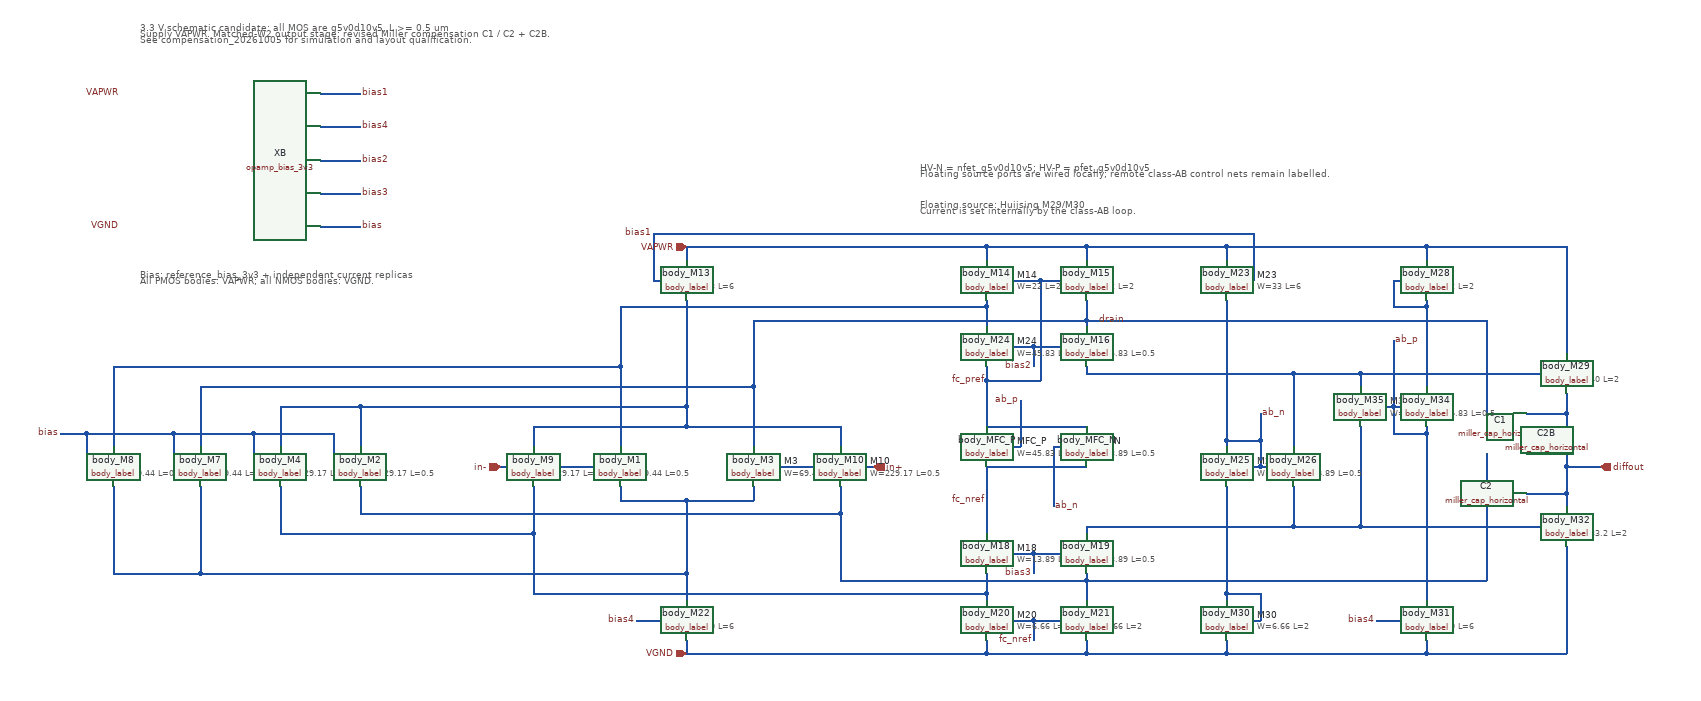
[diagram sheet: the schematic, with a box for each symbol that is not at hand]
v {xschem version=3.4.5 file_version=1.2
}
G {}
K {}
V {}
S {}
E {}
N -230 -60 -230 -30 {
lab=#net1}
N 0 -60 230 -60 {
lab=#net1}
N 230 -60 230 -30 {
lab=#net1}
N 0 -90 0 -60 {
lab=#net1}
N -490 -90 0 -90 {
lab=#net1}
N -490 -90 -490 -30 {
lab=#net1}
N -610 -90 -490 -90 {
lab=#net1}
N -610 -90 -610 -30 {
lab=#net1}
N -100 -150 -100 -30 {
lab=#net2}
N -860 -150 -100 -150 {
lab=#net2}
N -860 -150 -860 -30 {
lab=#net2}
N -730 -120 -730 -30 {
lab=drain}
N -730 -120 100 -120 {
lab=drain}
N 100 -120 100 -30 {
lab=drain}
N -100 30 -100 50 {
lab=#net3}
N 0 50 0 160 {
lab=#net3}
N -730 160 0 160 {
lab=#net3}
N -730 30 -730 160 {
lab=#net3}
N -280 0 -240 0 {
lab=in-}
N -240 0 -240 10 {
lab=in-}
N -240 10 -220 10 {
lab=in-}
N -220 10 -220 0 {
lab=in-}
N -220 0 -140 0 {
lab=in-}

N -490 70 230 70 {
lab=#net4}
N 230 70 230 170 {
lab=#net4}
N -610 30 -610 100 {
lab=#net5}
N -610 100 -230 100 {
lab=#net5}
N -230 30 -230 100 {
lab=#net5}
N 0 -250 0 -90 {
lab=#net1}
N 530 -280 560 -280 {
lab=#net6}
N 450 -240 450 -200 {
lab=#net2}
N 600 -220 600 -210 {
lab=drain}
N 530 -280 530 -130 {
lab=#net6}
N 450 190 450 200 {
lab=#net5}
N 600 170 600 200 {
lab=#net4}
N 0 160 0 200 {
lab=#net3}
N 0 260 0 280 {
lab=VGND}
N 450 280 600 280 {
lab=VGND}
N 600 260 600 280 {
lab=VGND}
N 450 260 450 280 {
lab=VGND}
N 450 -330 450 -310 {
lab=VAPWR}
N 450 -330 600 -330 {
lab=VAPWR}
N 600 -330 600 -310 {
lab=VAPWR}
N 600 -330 810 -330 {
lab=VAPWR}
N 810 -330 810 -310 {
lab=VAPWR}
N 810 -330 1110 -330 {
lab=VAPWR}
N 1060 -280 1070 -280 {
lab=#net7}
N 1060 -280 1060 -240 {
lab=#net7}
N 1060 -240 1110 -240 {
lab=#net7}
N 1110 -250 1110 -240 {
lab=#net7}
N 810 -250 810 -40 {
lab=#net8}
N 860 0 870 0 {
lab=#net8}
N 860 -40 860 0 {
lab=#net8}
N 810 -40 860 -40 {
lab=#net8}
N 1060 -90 1070 -90 {
lab=#net9}
N 1110 -240 1110 -120 {
lab=#net7}
N 1060 -90 1060 -50 {
lab=#net9}
N 1060 -50 1110 -50 {
lab=#net9}
N 1110 -60 1110 -50 {
lab=#net9}
N 450 -130 530 -130 {
lab=#net6}
N 1110 -330 1110 -310 {
lab=VAPWR}
N 600 -150 600 -140 {
lab=#net10}
N 1010 -140 1280 -140 {
lab=#net10}
N -230 -60 0 -60 {
lab=#net1}
N -100 50 0 50 {
lab=#net3}
N 490 -280 530 -280 {
lab=#net6}
N 0 280 450 280 {
lab=VGND}
N 450 -150 450 -130 {
lab=#net6}
N 810 -40 810 -30 {
lab=#net8}
N 810 190 810 200 {
lab=#net11}
N 600 280 810 280 {
lab=VGND}
N 810 260 810 280 {
lab=VGND}
N 1110 -50 1110 200 {
lab=#net9}
N 1110 280 1320 280 {
lab=VGND}
N 1320 120 1320 280 {
lab=VGND}
N 1320 40 1320 60 {
lab=diffout}
N 1320 -330 1320 -170 {
lab=VAPWR}
N 1110 -330 1320 -330 {
lab=VAPWR}
N 1110 260 1110 280 {
lab=VGND}
N 850 -350 850 -280 {
lab=bias1}
N -50 -350 850 -350 {
lab=bias1}
N 0 -330 0 -310 {
lab=VAPWR}
N 0 -330 450 -330 {
lab=VAPWR}
N -50 -350 -50 -280 {
lab=bias1}
N -50 -280 -40 -280 {
lab=bias1}
N 600 90 600 100 {
lab=#net12}
N 600 90 910 90 {
lab=#net12}
N 910 30 910 90 {
lab=#net12}
N 1010 -60 1010 90 {
lab=#net12}
N 850 230 860 230 {
lab=#net11}
N 860 190 860 230 {
lab=#net11}
N 810 190 860 190 {
lab=#net11}
N 600 170 1200 170 {
lab=#net4}
N 600 -220 1200 -220 {
lab=drain}
N 1010 -140 1010 -120 {
lab=#net10}
N 910 -140 910 -30 {
lab=#net10}
N 140 0 220 0 {
lab=in+}
N 220 0 220 10 {
lab=in+}
N 220 10 240 10 {
lab=in+}
N 240 10 240 0 {
lab=in+}
N 240 0 280 0 {
lab=in+}

N 100 -220 100 -120 {
lab=drain}
N 100 -220 600 -220 {
lab=drain}
N -100 -240 -100 -150 {
lab=#net2}
N -100 -240 450 -240 {
lab=#net2}
N -230 100 -230 190 {
lab=#net5}
N -230 190 450 190 {
lab=#net5}
N 0 50 100 50 {
lab=#net3}
N 100 30 100 50 {
lab=#net3}
N -490 30 -490 70 {
lab=#net4}
N 230 30 230 70 {
lab=#net4}
N 810 280 1110 280 {
lab=VGND}
N 910 90 1010 90 {
lab=#net12}
N 810 30 810 190 {
lab=#net11}
N 600 160 600 170 {
lab=#net4}
N 600 -250 600 -220 {
lab=drain}
N 910 -140 1010 -140 {
lab=#net10}
N 600 -140 910 -140 {
lab=#net10}
N 450 -250 450 -240 {
lab=#net2}
N 450 160 450 190 {
lab=#net5}
N -860 30 -860 160 {
lab=#net3}
N -860 160 -730 160 {
lab=#net3}
N 1200 40 1200 170 {
lab=#net4}
N 1260 40 1320 40 {
lab=diffout}
N 1200 -220 1200 -80 {
lab=drain}
N 1260 -80 1320 -80 {
lab=diffout}
N 1320 0 1370 0 {
lab=diffout}
N 1320 0 1320 40 {
lab=diffout}
N 1320 -110 1320 -80 {
lab=diffout}
N 1320 -80 1320 0 {
lab=diffout}
N 230 170 600 170 {
lab=#net4}
N 1010 90 1280 90 {
lab=#net12}
N 1050 -90 1060 -90 {
lab=#net9}
N 850 0 860 -0 {
lab=#net8}
N 490 -180 520 -180 {lab=bias2}
N 520 -180 560 -180 {lab=bias2}
N 520 -180 520 -150 {lab=bias2}
N 490 130 520 130 {lab=bias3}
N 520 130 560 130 {lab=bias3}
N 520 130 520 160 {lab=bias3}
N 490 230 520 230 {lab=fc_nref}
N 520 230 560 230 {lab=fc_nref}
N 520 230 520 260 {lab=fc_nref}
N -550 -560 -490 -560 {lab=bias1}
N -550 -510 -490 -510 {lab=bias4}
N -550 -460 -490 -460 {lab=bias2}
N -550 -410 -490 -410 {lab=bias3}
N -550 -360 -490 -360 {lab=bias}
N -40 230 -75 230 {lab=bias4}
N 1070 230 1035 230 {lab=bias4}
N 450 -130 450 -60 {lab=fc_pref}
N 450 -60 600 -60 {lab=fc_pref}
N 450 0 600 0 {lab=fc_nref}
N 450 0 450 50 {lab=fc_nref}
N 450 50 450 100 {lab=fc_nref}
N 490 -30 500 -30 {lab=ab_p}
N 500 -30 500 -100 {lab=ab_p}
N 560 -30 550 -30 {lab=ab_n}
N 550 -30 550 60 {lab=ab_n}
N 860 -40 860 -80 {lab=ab_n}
N 1060 -90 1060 -190 {lab=ab_p}
N -940 -50 -900 -50 {lab=bias}
N -900 -50 -770 -50 {lab=bias}
N -770 -50 -650 -50 {lab=bias}
N -650 -50 -530 -50 {lab=bias}
N -900 -50 -900 0 {lab=bias}
N -770 -50 -770 0 {lab=bias}
N -650 -50 -650 0 {lab=bias}
N -530 -50 -530 0 {lab=bias}
C {hv_nmos.sym} -120 0 0 0 {name=M1
L=0.5
W=69.44
nf=5
mult=1
body=VGND
ad="'int((nf+1)/2) * W/nf * 0.29'" 
pd="'2*int((nf+1)/2) * (W/nf + 0.29)'"
as="'int((nf+2)/2) * W/nf * 0.29'" 
ps="'2*int((nf+2)/2) * (W/nf + 0.29)'"
nrd="'0.29 / W'" nrs="'0.29 / W'"
sa=0 sb=0 sd=0
model=nfet_g5v0d10v5
spiceprefix=X
}
C {hv_nmos.sym} 120 0 0 1 {name=M3
L=0.5
W=69.44
nf=5
mult=1
body=VGND
ad="'int((nf+1)/2) * W/nf * 0.29'" 
pd="'2*int((nf+1)/2) * (W/nf + 0.29)'"
as="'int((nf+2)/2) * W/nf * 0.29'" 
ps="'2*int((nf+2)/2) * (W/nf + 0.29)'"
nrd="'0.29 / W'" nrs="'0.29 / W'"
sa=0 sb=0 sd=0
model=nfet_g5v0d10v5
spiceprefix=X
}
C {hv_nmos.sym} -750 0 0 0 {name=M7
L=0.5
W=69.44
nf=5
mult=1
body=VGND
ad="'int((nf+1)/2) * W/nf * 0.29'" 
pd="'2*int((nf+1)/2) * (W/nf + 0.29)'"
as="'int((nf+2)/2) * W/nf * 0.29'" 
ps="'2*int((nf+2)/2) * (W/nf + 0.29)'"
nrd="'0.29 / W'" nrs="'0.29 / W'"
sa=0 sb=0 sd=0
model=nfet_g5v0d10v5
spiceprefix=X
}
C {hv_nmos.sym} -880 0 0 0 {name=M8
L=0.5
W=69.44
nf=5
mult=1
body=VGND
ad="'int((nf+1)/2) * W/nf * 0.29'" 
pd="'2*int((nf+1)/2) * (W/nf + 0.29)'"
as="'int((nf+2)/2) * W/nf * 0.29'" 
ps="'2*int((nf+2)/2) * (W/nf + 0.29)'"
nrd="'0.29 / W'" nrs="'0.29 / W'"
sa=0 sb=0 sd=0
model=nfet_g5v0d10v5
spiceprefix=X
}
C {devices/ipin.sym} -280 0 0 0 {name=p1 lab=in-}
C {devices/ipin.sym} 280 0 0 1 {name=p2 lab=in+

}
C {hv_nmos.sym} 470 130 0 1 {name=M18
L=0.5
W=13.89
nf=1
mult=1
body=VGND
ad="'int((nf+1)/2) * W/nf * 0.29'" 
pd="'2*int((nf+1)/2) * (W/nf + 0.29)'"
as="'int((nf+2)/2) * W/nf * 0.29'" 
ps="'2*int((nf+2)/2) * (W/nf + 0.29)'"
nrd="'0.29 / W'" nrs="'0.29 / W'"
sa=0 sb=0 sd=0
model=nfet_g5v0d10v5
spiceprefix=X
}
C {hv_nmos.sym} 580 130 0 0 {name=M19
L=0.5
W=13.89
nf=1
mult=1
body=VGND
ad="'int((nf+1)/2) * W/nf * 0.29'" 
pd="'2*int((nf+1)/2) * (W/nf + 0.29)'"
as="'int((nf+2)/2) * W/nf * 0.29'" 
ps="'2*int((nf+2)/2) * (W/nf + 0.29)'"
nrd="'0.29 / W'" nrs="'0.29 / W'"
sa=0 sb=0 sd=0
model=nfet_g5v0d10v5
spiceprefix=X
}
C {hv_nmos.sym} 470 230 0 1 {name=M20
L=2
W=6.66
nf=2
mult=1
body=VGND
ad="'int((nf+1)/2) * W/nf * 0.29'" 
pd="'2*int((nf+1)/2) * (W/nf + 0.29)'"
as="'int((nf+2)/2) * W/nf * 0.29'" 
ps="'2*int((nf+2)/2) * (W/nf + 0.29)'"
nrd="'0.29 / W'" nrs="'0.29 / W'"
sa=0 sb=0 sd=0
model=nfet_g5v0d10v5
spiceprefix=X
}
C {hv_nmos.sym} 580 230 0 0 {name=M21
L=2
W=6.66
nf=2
mult=1
body=VGND
ad="'int((nf+1)/2) * W/nf * 0.29'" 
pd="'2*int((nf+1)/2) * (W/nf + 0.29)'"
as="'int((nf+2)/2) * W/nf * 0.29'" 
ps="'2*int((nf+2)/2) * (W/nf + 0.29)'"
nrd="'0.29 / W'" nrs="'0.29 / W'"
sa=0 sb=0 sd=0
model=nfet_g5v0d10v5
spiceprefix=X
}
C {hv_nmos.sym} -20 230 0 0 {name=M22
L=6
W=10
nf=1
mult=1
body=VGND
ad="'int((nf+1)/2) * W/nf * 0.29'" 
pd="'2*int((nf+1)/2) * (W/nf + 0.29)'"
as="'int((nf+2)/2) * W/nf * 0.29'" 
ps="'2*int((nf+2)/2) * (W/nf + 0.29)'"
nrd="'0.29 / W'" nrs="'0.29 / W'"
sa=0 sb=0 sd=0
model=nfet_g5v0d10v5
spiceprefix=X
}
C {hv_nmos.sym} 830 0 0 1 {name=M25
L=0.5
W=13.89
nf=1
mult=1
body=VGND
ad="'int((nf+1)/2) * W/nf * 0.29'" 
pd="'2*int((nf+1)/2) * (W/nf + 0.29)'"
as="'int((nf+2)/2) * W/nf * 0.29'" 
ps="'2*int((nf+2)/2) * (W/nf + 0.29)'"
nrd="'0.29 / W'" nrs="'0.29 / W'"
sa=0 sb=0 sd=0
model=nfet_g5v0d10v5
spiceprefix=X
}
C {hv_nmos.sym} 890 0 0 0 {name=M26
L=0.5
W=13.89
nf=1
mult=1
body=VGND
ad="'int((nf+1)/2) * W/nf * 0.29'" 
pd="'2*int((nf+1)/2) * (W/nf + 0.29)'"
as="'int((nf+2)/2) * W/nf * 0.29'" 
ps="'2*int((nf+2)/2) * (W/nf + 0.29)'"
nrd="'0.29 / W'" nrs="'0.29 / W'"
sa=0 sb=0 sd=0
model=nfet_g5v0d10v5
spiceprefix=X
}
C {hv_nmos.sym} 830 230 0 1 {name=M30
L=2
W=6.66
nf=2
mult=1
body=VGND
ad="'int((nf+1)/2) * W/nf * 0.29'" 
pd="'2*int((nf+1)/2) * (W/nf + 0.29)'"
as="'int((nf+2)/2) * W/nf * 0.29'" 
ps="'2*int((nf+2)/2) * (W/nf + 0.29)'"
nrd="'0.29 / W'" nrs="'0.29 / W'"
sa=0 sb=0 sd=0
model=nfet_g5v0d10v5
spiceprefix=X
}
C {hv_nmos.sym} 1090 230 0 0 {name=M31
L=6
W=10
nf=1
mult=1
body=VGND
ad="'int((nf+1)/2) * W/nf * 0.29'" 
pd="'2*int((nf+1)/2) * (W/nf + 0.29)'"
as="'int((nf+2)/2) * W/nf * 0.29'" 
ps="'2*int((nf+2)/2) * (W/nf + 0.29)'"
nrd="'0.29 / W'" nrs="'0.29 / W'"
sa=0 sb=0 sd=0
model=nfet_g5v0d10v5
spiceprefix=X
}
C {hv_nmos.sym} 1300 90 0 0 {name=M32
L=2
W=133.2
nf=40
mult=1
body=VGND
ad="'int((nf+1)/2) * W/nf * 0.29'" 
pd="'2*int((nf+1)/2) * (W/nf + 0.29)'"
as="'int((nf+2)/2) * W/nf * 0.29'" 
ps="'2*int((nf+2)/2) * (W/nf + 0.29)'"
nrd="'0.29 / W'" nrs="'0.29 / W'"
sa=0 sb=0 sd=0
model=nfet_g5v0d10v5
spiceprefix=X
}
C {miller_cap_horizontal.sym} 1230 -80 0 0 {name=C1 model=cap_mim_m3_1 W=18 L=18 MF=1 spiceprefix=X}
C {miller_cap_horizontal.sym} 1230 40 0 0 {name=C2 model=cap_mim_m3_1 W=30 L=30 MF=1 spiceprefix=X}
N 1200 -20 1200 40 {lab=#net4}
N 1260 -20 1320 -20 {lab=diffout}
C {miller_cap_horizontal.sym} 1230 -20 0 0 {name=C2B model=cap_mim_m3_1 W=30 L=10 MF=1 spiceprefix=X}
C {devices/opin.sym} 1370 0 0 0 {name=p3 lab=diffout}
C {devices/iopin.sym} 0 -330 0 0 {name=p4 lab=VAPWR}
C {devices/iopin.sym} 0 280 0 0 {name=p5 lab=VGND}
C {hv_pmos.sym} -20 -280 0 0 {name=M13
L=6
W=33
body=VAPWR
nf=1
mult=1
ad="'int((nf+1)/2) * W/nf * 0.29'" 
pd="'2*int((nf+1)/2) * (W/nf + 0.29)'"
as="'int((nf+2)/2) * W/nf * 0.29'" 
ps="'2*int((nf+2)/2) * (W/nf + 0.29)'"
nrd="'0.29 / W'" nrs="'0.29 / W'"
sa=0 sb=0 sd=0
model=pfet_g5v0d10v5
spiceprefix=X
}
C {hv_pmos.sym} 470 -280 0 1 {name=M14
L=2
W=22
body=VAPWR
nf=2
mult=1
ad="'int((nf+1)/2) * W/nf * 0.29'" 
pd="'2*int((nf+1)/2) * (W/nf + 0.29)'"
as="'int((nf+2)/2) * W/nf * 0.29'" 
ps="'2*int((nf+2)/2) * (W/nf + 0.29)'"
nrd="'0.29 / W'" nrs="'0.29 / W'"
sa=0 sb=0 sd=0
model=pfet_g5v0d10v5
spiceprefix=X
}
C {hv_pmos.sym} 580 -280 0 0 {name=M15
L=2
W=22
body=VAPWR
nf=2
mult=1
ad="'int((nf+1)/2) * W/nf * 0.29'" 
pd="'2*int((nf+1)/2) * (W/nf + 0.29)'"
as="'int((nf+2)/2) * W/nf * 0.29'" 
ps="'2*int((nf+2)/2) * (W/nf + 0.29)'"
nrd="'0.29 / W'" nrs="'0.29 / W'"
sa=0 sb=0 sd=0
model=pfet_g5v0d10v5
spiceprefix=X
}
C {hv_pmos.sym} 580 -180 0 0 {name=M16
L=0.5
W=45.83
body=VAPWR
nf=1
mult=1
ad="'int((nf+1)/2) * W/nf * 0.29'" 
pd="'2*int((nf+1)/2) * (W/nf + 0.29)'"
as="'int((nf+2)/2) * W/nf * 0.29'" 
ps="'2*int((nf+2)/2) * (W/nf + 0.29)'"
nrd="'0.29 / W'" nrs="'0.29 / W'"
sa=0 sb=0 sd=0
model=pfet_g5v0d10v5
spiceprefix=X
}
C {hv_pmos.sym} 830 -280 0 1 {name=M23
L=6
W=33
body=VAPWR
nf=1
mult=1
ad="'int((nf+1)/2) * W/nf * 0.29'" 
pd="'2*int((nf+1)/2) * (W/nf + 0.29)'"
as="'int((nf+2)/2) * W/nf * 0.29'" 
ps="'2*int((nf+2)/2) * (W/nf + 0.29)'"
nrd="'0.29 / W'" nrs="'0.29 / W'"
sa=0 sb=0 sd=0
model=pfet_g5v0d10v5
spiceprefix=X
}
C {hv_pmos.sym} 470 -180 0 1 {name=M24
L=0.5
W=45.83
body=VAPWR
nf=1
mult=1
ad="'int((nf+1)/2) * W/nf * 0.29'" 
pd="'2*int((nf+1)/2) * (W/nf + 0.29)'"
as="'int((nf+2)/2) * W/nf * 0.29'" 
ps="'2*int((nf+2)/2) * (W/nf + 0.29)'"
nrd="'0.29 / W'" nrs="'0.29 / W'"
sa=0 sb=0 sd=0
model=pfet_g5v0d10v5
spiceprefix=X
}
C {hv_pmos.sym} 1090 -280 0 0 {name=M28
L=2
W=22
body=VAPWR
nf=2
mult=1
ad="'int((nf+1)/2) * W/nf * 0.29'" 
pd="'2*int((nf+1)/2) * (W/nf + 0.29)'"
as="'int((nf+2)/2) * W/nf * 0.29'" 
ps="'2*int((nf+2)/2) * (W/nf + 0.29)'"
nrd="'0.29 / W'" nrs="'0.29 / W'"
sa=0 sb=0 sd=0
model=pfet_g5v0d10v5
spiceprefix=X
}
C {hv_pmos.sym} 1300 -140 0 0 {name=M29
L=2
W=440
body=VAPWR
nf=40
mult=1
ad="'int((nf+1)/2) * W/nf * 0.29'" 
pd="'2*int((nf+1)/2) * (W/nf + 0.29)'"
as="'int((nf+2)/2) * W/nf * 0.29'" 
ps="'2*int((nf+2)/2) * (W/nf + 0.29)'"
nrd="'0.29 / W'" nrs="'0.29 / W'"
sa=0 sb=0 sd=0
model=pfet_g5v0d10v5
spiceprefix=X
}
C {hv_pmos.sym} 1090 -90 0 0 {name=M34
L=0.5
W=45.83
body=VAPWR
nf=1
mult=1
ad="'int((nf+1)/2) * W/nf * 0.29'" 
pd="'2*int((nf+1)/2) * (W/nf + 0.29)'"
as="'int((nf+2)/2) * W/nf * 0.29'" 
ps="'2*int((nf+2)/2) * (W/nf + 0.29)'"
nrd="'0.29 / W'" nrs="'0.29 / W'"
sa=0 sb=0 sd=0
model=pfet_g5v0d10v5
spiceprefix=X
}
C {hv_pmos.sym} 1030 -90 0 1 {name=M35
L=0.5
W=45.83
body=VAPWR
nf=1
mult=1
ad="'int((nf+1)/2) * W/nf * 0.29'" 
pd="'2*int((nf+1)/2) * (W/nf + 0.29)'"
as="'int((nf+2)/2) * W/nf * 0.29'" 
ps="'2*int((nf+2)/2) * (W/nf + 0.29)'"
nrd="'0.29 / W'" nrs="'0.29 / W'"
sa=0 sb=0 sd=0
model=pfet_g5v0d10v5
spiceprefix=X
}
C {hv_pmos.sym} -510 0 0 0 {name=M2
L=0.5
W=229.17
body=VAPWR
nf=10
mult=2
ad="'int((nf+1)/2) * W/nf * 0.29'" 
pd="'2*int((nf+1)/2) * (W/nf + 0.29)'"
as="'int((nf+2)/2) * W/nf * 0.29'" 
ps="'2*int((nf+2)/2) * (W/nf + 0.29)'"
nrd="'0.29 / W'" nrs="'0.29 / W'"
sa=0 sb=0 sd=0
model=pfet_g5v0d10v5
spiceprefix=X
}
C {hv_pmos.sym} -630 0 0 0 {name=M4
L=0.5
W=229.17
body=VAPWR
nf=10
mult=2
ad="'int((nf+1)/2) * W/nf * 0.29'" 
pd="'2*int((nf+1)/2) * (W/nf + 0.29)'"
as="'int((nf+2)/2) * W/nf * 0.29'" 
ps="'2*int((nf+2)/2) * (W/nf + 0.29)'"
nrd="'0.29 / W'" nrs="'0.29 / W'"
sa=0 sb=0 sd=0
model=pfet_g5v0d10v5
spiceprefix=X
}
C {hv_pmos.sym} -250 0 0 0 {name=M9
L=0.5
W=229.17
body=VAPWR
nf=10
mult=2
ad="'int((nf+1)/2) * W/nf * 0.29'" 
pd="'2*int((nf+1)/2) * (W/nf + 0.29)'"
as="'int((nf+2)/2) * W/nf * 0.29'" 
ps="'2*int((nf+2)/2) * (W/nf + 0.29)'"
nrd="'0.29 / W'" nrs="'0.29 / W'"
sa=0 sb=0 sd=0
model=pfet_g5v0d10v5
spiceprefix=X
}
C {hv_pmos.sym} 250 0 0 1 {name=M10
L=0.5
W=229.17
body=VAPWR
nf=10
mult=2
ad="'int((nf+1)/2) * W/nf * 0.29'" 
pd="'2*int((nf+1)/2) * (W/nf + 0.29)'"
as="'int((nf+2)/2) * W/nf * 0.29'" 
ps="'2*int((nf+2)/2) * (W/nf + 0.29)'"
nrd="'0.29 / W'" nrs="'0.29 / W'"
sa=0 sb=0 sd=0
model=pfet_g5v0d10v5
spiceprefix=X
}
C {devices/lab_wire.sym} 660 -220 0 0 {name=p11 sig_type=std_logic lab=drain}
C {opamp_bias_3v3.sym} -700 -460 0 0 {name=XB}
C {devices/lab_pin.sym} -850 -560 0 0 {name=pb56 lab=VAPWR}
C {devices/lab_pin.sym} -850 -360 0 0 {name=pb57 lab=VGND}
C {devices/lab_pin.sym} 450 -130 0 0 {name=pb77 lab=fc_pref}
C {hv_pmos_floating.sym} 470 -30 0 1 {name=MFC_P
L=0.5
W=45.83
nf=1
mult=1
body=VAPWR
ad="'int((nf+1)/2) * W/nf * 0.29'"
as="'int((nf+2)/2) * W/nf * 0.29'"
pd="'2*int((nf+1)/2) * (W/nf + 0.29)'"
ps="'2*int((nf+2)/2) * (W/nf + 0.29)'"
nrd="'0.29 / W'" nrs="'0.29 / W'"
sa=0 sb=0 sd=0
model=pfet_g5v0d10v5
spiceprefix=X}
C {hv_nmos_floating.sym} 580 -30 0 0 {name=MFC_N
L=0.5
W=13.89
nf=1
mult=1
body=VGND
ad="'int((nf+1)/2) * W/nf * 0.29'"
as="'int((nf+2)/2) * W/nf * 0.29'"
pd="'2*int((nf+1)/2) * (W/nf + 0.29)'"
ps="'2*int((nf+2)/2) * (W/nf + 0.29)'"
nrd="'0.29 / W'" nrs="'0.29 / W'"
sa=0 sb=0 sd=0
model=nfet_g5v0d10v5
spiceprefix=X}
C {body_label.sym} -100 0 0 0 {name=body_M1 lab=VGND}
C {body_label.sym} 100 0 0 1 {name=body_M3 lab=VGND}
C {body_label.sym} -730 0 0 0 {name=body_M7 lab=VGND}
C {body_label.sym} -860 0 0 0 {name=body_M8 lab=VGND}
C {body_label.sym} 450 130 0 1 {name=body_M18 lab=VGND}
C {body_label.sym} 600 130 0 0 {name=body_M19 lab=VGND}
C {body_label.sym} 450 230 0 1 {name=body_M20 lab=VGND}
C {body_label.sym} 600 230 0 0 {name=body_M21 lab=VGND}
C {body_label.sym} 0 230 0 0 {name=body_M22 lab=VGND}
C {body_label.sym} 810 0 0 1 {name=body_M25 lab=VGND}
C {body_label.sym} 910 0 0 0 {name=body_M26 lab=VGND}
C {body_label.sym} 810 230 0 1 {name=body_M30 lab=VGND}
C {body_label.sym} 1110 230 0 0 {name=body_M31 lab=VGND}
C {body_label.sym} 1320 90 0 0 {name=body_M32 lab=VGND}
C {body_label.sym} 0 -280 0 0 {name=body_M13 lab=VAPWR}
C {body_label.sym} 450 -280 0 1 {name=body_M14 lab=VAPWR}
C {body_label.sym} 600 -280 0 0 {name=body_M15 lab=VAPWR}
C {body_label.sym} 600 -180 0 0 {name=body_M16 lab=VAPWR}
C {body_label.sym} 810 -280 0 1 {name=body_M23 lab=VAPWR}
C {body_label.sym} 450 -180 0 1 {name=body_M24 lab=VAPWR}
C {body_label.sym} 1110 -280 0 0 {name=body_M28 lab=VAPWR}
C {body_label.sym} 1320 -140 0 0 {name=body_M29 lab=VAPWR}
C {body_label.sym} 1110 -90 0 0 {name=body_M34 lab=VAPWR}
C {body_label.sym} 1010 -90 0 1 {name=body_M35 lab=VAPWR}
C {body_label.sym} -490 0 0 0 {name=body_M2 lab=VAPWR}
C {body_label.sym} -610 0 0 0 {name=body_M4 lab=VAPWR}
C {body_label.sym} -230 0 0 0 {name=body_M9 lab=VAPWR}
C {body_label.sym} 230 0 0 1 {name=body_M10 lab=VAPWR}
T {Floating source: Huijsing M29/M30
Current is set internally by the class-AB loop.} 350 -405 0 0 0.24 0.24 {}
T {Bias: reference_bias_3v3 + independent current replicas
All PMOS bodies: VAPWR; all NMOS bodies: VGND.} -820 -300 0 0 0.23 0.23 {}
C {body_label.sym} 450 -30 0 1 {name=body_MFC_P lab=VAPWR}
C {body_label.sym} 600 -30 0 0 {name=body_MFC_N lab=VGND}

C {devices/lab_pin.sym} 520 -150 0 0 {name=hv_bias2 lab=bias2}
C {devices/lab_pin.sym} 520 160 0 0 {name=hv_bias3 lab=bias3}
C {devices/lab_pin.sym} 520 260 0 0 {name=hv_fc_nref lab=fc_nref}
T {3.3 V schematic candidate: all MOS are g5v0d10v5, L >= 0.5 um
Supply VAPWR. Matched-W2 output stage; revised Miller compensation C1 / C2 + C2B.
See compensation_20261005 for simulation and layout qualification.} -820 -670 0 0 0.23 0.23 {}
C {devices/lab_pin.sym} -490 -560 0 1 {name=pb58 lab=bias1}
C {devices/lab_pin.sym} -490 -510 0 1 {name=pb59 lab=bias4}
C {devices/lab_pin.sym} -490 -460 0 1 {name=pb60 lab=bias2}
C {devices/lab_pin.sym} -490 -410 0 1 {name=pb61 lab=bias3}
C {devices/lab_pin.sym} -490 -360 0 1 {name=pb62 lab=bias}
C {devices/lab_pin.sym} -75 230 0 0 {name=pb64 lab=bias4}
C {devices/lab_pin.sym} 1035 230 0 0 {name=pb65 lab=bias4}
C {devices/lab_pin.sym} -50 -350 0 0 {name=pb63 lab=bias1}
C {devices/lab_pin.sym} 500 -100 0 0 {name=fc_gate_p lab=ab_p}
C {devices/lab_pin.sym} 550 60 0 1 {name=fc_gate_n lab=ab_n}
C {devices/lab_pin.sym} 450 50 0 0 {name=pb76 lab=fc_nref}
C {devices/lab_pin.sym} 860 -80 0 1 {name=pb78 lab=ab_n}
C {devices/lab_pin.sym} 1060 -190 0 1 {name=pb79 lab=ab_p}
T {HV-N = nfet_g5v0d10v5; HV-P = pfet_g5v0d10v5
Floating source ports are wired locally; remote class-AB control nets remain labelled.} 350 -460 0 0 0.23 0.23 {}
C {devices/lab_pin.sym} -940 -50 0 0 {name=spillover_bias_bus lab=bias}
